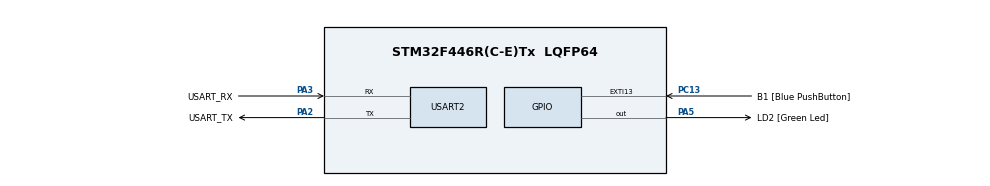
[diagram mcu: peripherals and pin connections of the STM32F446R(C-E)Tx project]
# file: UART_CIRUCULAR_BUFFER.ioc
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Mcu.Family=STM32F4
Mcu.Name=STM32F446R(C-E)Tx
Mcu.Package=LQFP64
NVIC.PriorityGroup=NVIC_PRIORITYGROUP_0
NVIC.USART2_IRQn=true\:0\:0\:false\:false\:true\:true\:true\:true
PA13.GPIO_Label=TMS
PA13.Mode=Serial_Wire
PA13.Signal=SYS_JTMS-SWDIO
PA14.GPIO_Label=TCK
PA14.Mode=Serial_Wire
PA14.Signal=SYS_JTCK-SWCLK
PA2.GPIO_Label=USART_TX
PA2.Mode=Asynchronous
PA2.Signal=USART2_TX
PA3.GPIO_Label=USART_RX
PA3.Mode=Asynchronous
PA3.Signal=USART2_RX
PA5.GPIO_Label=LD2 [Green Led]
PA5.Signal=GPIO_Output
PB3.GPIO_Label=SWO
PB3.Signal=SYS_JTDO-SWO
PC13.GPIO_Label=B1 [Blue PushButton]
PC13.GPIO_ModeDefaultEXTI=GPIO_MODE_IT_FALLING
PC13.Signal=GPXTI13
PC14-OSC32_IN.Mode=LSE-External-Oscillator
PC14-OSC32_IN.Signal=RCC_OSC32_IN
PC15-OSC32_OUT.Mode=LSE-External-Oscillator
PC15-OSC32_OUT.Signal=RCC_OSC32_OUT
PH0-OSC_IN.Mode=HSE-External-Oscillator
PH0-OSC_IN.Signal=RCC_OSC_IN
PH1-OSC_OUT.Mode=HSE-External-Oscillator
PH1-OSC_OUT.Signal=RCC_OSC_OUT
ProjectManager.HeapSize=0x200
ProjectManager.StackSize=0x400
ProjectManager.TargetToolchain=STM32CubeIDE
RCC.48MHZClocksFreq_Value=84000000
RCC.AHBFreq_Value=84000000
RCC.APB1CLKDivider=RCC_HCLK_DIV2
RCC.APB1Freq_Value=42000000
RCC.APB1TimFreq_Value=84000000
RCC.APB2Freq_Value=84000000
RCC.APB2TimFreq_Value=84000000
RCC.CortexFreq_Value=84000000
RCC.FLatency-AdvancedSettings=FLASH_LATENCY_2
RCC.HCLKFreq_Value=84000000
RCC.HSE_VALUE=8000000
RCC.HSI_VALUE=16000000
RCC.PLLN=336
RCC.PLLP=RCC_PLLP_DIV4
RCC.SYSCLKFreq_VALUE=84000000
RCC.SYSCLKSource=RCC_SYSCLKSOURCE_PLLCLK
RCC.USBFreq_Value=168000000
RCC.VCOOutputFreq_Value=336000000
USART2.VirtualMode=VM_ASYNC
board=NUCLEO-F446RE

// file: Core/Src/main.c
/* USER CODE BEGIN Header */
/**
  ******************************************************************************
  * @file           : main.c
  * @brief          : Main program body
  ******************************************************************************
  * @attention
  *
  * Copyright (c) 2025 STMicroelectronics.
  * All rights reserved.
  *
  * This software is licensed under terms that can be found in the LICENSE file
  * in the root directory of this software component.
  * If no LICENSE file comes with this software, it is provided AS-IS.
  *
  ******************************************************************************
  */
/* USER CODE END Header */
#include "main.h"

/* USER CODE BEGIN Includes */
#include <string.h>
#define UART_BUFFER_SIZE 128

/* USER CODE END Includes */

UART_HandleTypeDef huart2;
uint8_t rx_byte;

void SystemClock_Config(void);
static void MX_GPIO_Init(void);
static void MX_USART2_UART_Init(void);
/* USER CODE BEGIN PFP */
/* Circular buffer struct */
/* Circular buffer structure */
typedef struct {
    uint8_t buffer[UART_BUFFER_SIZE];
    volatile uint16_t head;
    volatile uint16_t tail;
} CircularBuffer_t;

CircularBuffer_t uart_rx_buffer;

/* Function Prototypes */
void SystemClock_Config(void);
static void MX_GPIO_Init(void);
static void MX_USART2_UART_Init(void);

/* Push to circular buffer */
void CircularBuffer_Push(CircularBuffer_t *cb, uint8_t data) {
    uint16_t next = (cb->head + 1) % UART_BUFFER_SIZE;
    if (next != cb->tail) {
        cb->buffer[cb->head] = data;
        cb->head = next;
    }
}

/* Pop from circular buffer */
int CircularBuffer_Pop(CircularBuffer_t *cb, uint8_t *data) {
    if (cb->head == cb->tail)
        return 0;
    *data = cb->buffer[cb->tail];
    cb->tail = (cb->tail + 1) % UART_BUFFER_SIZE;
    return 1;
}

/* UART receive complete callback */
void HAL_UART_RxCpltCallback(UART_HandleTypeDef *huart) {
    if (huart->Instance == USART2) {
        CircularBuffer_Push(&uart_rx_buffer, rx_byte);
        HAL_UART_Receive_IT(&huart2, &rx_byte, 1);  // Restart interrupt
    }
}
/* USER CODE END PFP */

int main(void)
{

  /* MCU Configuration--------------------------------------------------------*/

  /* Reset of all peripherals, Initializes the Flash interface and the Systick. */
  HAL_Init();

  /* Configure the system clock */
  SystemClock_Config();

  /* Initialize all configured peripherals */
  MX_GPIO_Init();
  MX_USART2_UART_Init();
  /* USER CODE BEGIN 2 */

  char *hello_msg = "UART Ready!\r\n";
  HAL_UART_Transmit(&huart2, (uint8_t *)hello_msg, strlen(hello_msg), HAL_MAX_DELAY);

  HAL_UART_Receive_IT(&huart2, &rx_byte, 1);

  uint8_t byte;
  /* USER CODE END 2 */

  /* Infinite loop */
  while (1)
  {
	  if (CircularBuffer_Pop(&uart_rx_buffer, &byte)) {
	      HAL_UART_Transmit(&huart2, &byte, 1, HAL_MAX_DELAY);
	      HAL_GPIO_TogglePin(GPIOA, GPIO_PIN_5);  // Optional LED toggle
	  }

  }
}

void SystemClock_Config(void)
{
  RCC_OscInitTypeDef RCC_OscInitStruct = {0};
  RCC_ClkInitTypeDef RCC_ClkInitStruct = {0};

  /** Configure the main internal regulator output voltage
  */
  __HAL_RCC_PWR_CLK_ENABLE();
  __HAL_PWR_VOLTAGESCALING_CONFIG(PWR_REGULATOR_VOLTAGE_SCALE3);

  /** Initializes the RCC Oscillators according to the specified parameters
  * in the RCC_OscInitTypeDef structure.
  */
  RCC_OscInitStruct.OscillatorType = RCC_OSCILLATORTYPE_HSI;
  RCC_OscInitStruct.HSIState = RCC_HSI_ON;
  RCC_OscInitStruct.HSICalibrationValue = RCC_HSICALIBRATION_DEFAULT;
  RCC_OscInitStruct.PLL.PLLState = RCC_PLL_NONE;
  if (HAL_RCC_OscConfig(&RCC_OscInitStruct) != HAL_OK)
  {
    Error_Handler();
  }

  /** Initializes the CPU, AHB and APB buses clocks
  */
  RCC_ClkInitStruct.ClockType = RCC_CLOCKTYPE_HCLK|RCC_CLOCKTYPE_SYSCLK
                              |RCC_CLOCKTYPE_PCLK1|RCC_CLOCKTYPE_PCLK2;
  RCC_ClkInitStruct.SYSCLKSource = RCC_SYSCLKSOURCE_HSI;
  RCC_ClkInitStruct.AHBCLKDivider = RCC_SYSCLK_DIV1;
  RCC_ClkInitStruct.APB1CLKDivider = RCC_HCLK_DIV1;
  RCC_ClkInitStruct.APB2CLKDivider = RCC_HCLK_DIV1;

  if (HAL_RCC_ClockConfig(&RCC_ClkInitStruct, FLASH_LATENCY_0) != HAL_OK)
  {
    Error_Handler();
  }
}

static void MX_USART2_UART_Init(void)
{

  huart2.Instance = USART2;
  huart2.Init.BaudRate = 9600;
  huart2.Init.WordLength = UART_WORDLENGTH_8B;
  huart2.Init.StopBits = UART_STOPBITS_1;
  huart2.Init.Parity = UART_PARITY_NONE;
  huart2.Init.Mode = UART_MODE_TX_RX;
  huart2.Init.HwFlowCtl = UART_HWCONTROL_NONE;
  huart2.Init.OverSampling = UART_OVERSAMPLING_16;
  if (HAL_UART_Init(&huart2) != HAL_OK)
  {
    Error_Handler();
  }

}

static void MX_GPIO_Init(void)
{

  /* GPIO Ports Clock Enable */
  __HAL_RCC_GPIOC_CLK_ENABLE();
  __HAL_RCC_GPIOH_CLK_ENABLE();
  __HAL_RCC_GPIOA_CLK_ENABLE();

}

void Error_Handler(void)
{
  __disable_irq();
  while (1)
  {
  }
}
